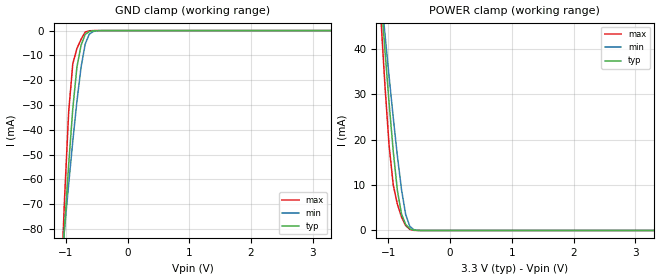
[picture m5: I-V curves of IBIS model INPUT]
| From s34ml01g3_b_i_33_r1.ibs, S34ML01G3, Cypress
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|   Model INPUT
[Model] INPUT
Model_type Input
Polarity   Non-Inverting
Vinl =  0.660V
Vinh =  2.640V
C_comp   2.860pF   2.840pF   2.890pF
[Model Spec]
Vinh   2.640V   2.160V   2.880V
Vinl   0.660V   0.540V   0.720V
[Temperature Range]   25.000   85.000   -40.000
[Voltage Range]   3.300V   2.700V   3.600V
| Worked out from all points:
|   GND clamp passes 1 mA (typ) near -0.66 V on its own axis
|   POWER clamp passes 1 mA (typ) near -0.70 V on its own axis
[GND_clamp]
|Voltage   I(typ)   I(min)   I(max)
-3.3V     -1.091A    -761mA     -1.739A
-1.089V   -106.4mA   -98.63mA   -110mA
-1.022V   -79.54mA   -80.06mA   -68.12mA
-955mV    -54.15mA   -61.98mA   -32.91mA
-888mV    -31.54mA   -44.64mA   -13.37mA
-821mV    -14.71mA   -28.56mA   -7.248mA
-754mV    -5.951mA   -14.81mA   -3.53mA
-687mV    -1.508mA   -5.409mA   -606.1uA
-620mV    -369.5uA   -1.421mA   -79.63uA
-553mV    -79.73uA   -350.6uA   -8.879uA
-486mV    -14.59uA   -85.42uA   -793.1nA
3.3V      0A         0A         0A
[POWER_clamp]
|Voltage   I(typ)   I(min)   I(max)
-3.3V     484mA      387mA      621.1mA
-1.122V   51.69mA    52.79mA    47mA
-1.055V   39.6mA     43.22mA    31.83mA
-988mV    28.05mA    33.88mA    18.67mA
-921mV    17.46mA    24.87mA    10.02mA
-854mV    8.817mA    16.42mA    5.78mA
-787mV    3.61mA     8.999mA    2.955mA
-720mV    1.342mA    3.534mA    1.088mA
-653mV    380.8uA    901.7uA    235uA
-586mV    72.64uA    176uA      28.35uA
-452mV    1.393uA    5.4uA      201.2nA
3.3V      0A         0A         3.891nA
